VERSION 5.8 ;
BUSBITCHARS "[]" ;
DIVIDERCHAR "/" ;

UNITS
  DATABASE MICRONS 1000 ;
END UNITS

MANUFACTURINGGRID 0.005 ;

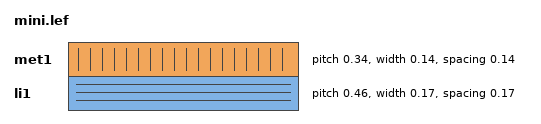
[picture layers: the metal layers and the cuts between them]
LAYER li1
  TYPE ROUTING ;
  DIRECTION HORIZONTAL ;
  PITCH 0.46 ;
  WIDTH 0.17 ;
  OFFSET 0.23 ;
  SPACING 0.17 ;
END li1

LAYER met1
  TYPE ROUTING ;
  DIRECTION VERTICAL ;
  PITCH 0.34 ;
  WIDTH 0.14 ;
  OFFSET 0.17 ;
  SPACING 0.14 ;
END met1

SITE unit
  CLASS CORE ;
  SIZE 0.46 BY 2.72 ;
  SYMMETRY Y ;
END unit

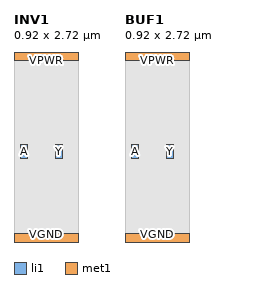
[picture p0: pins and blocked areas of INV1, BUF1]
MACRO INV1
  CLASS CORE ;
  ORIGIN 0 0 ;
  SIZE 0.92 BY 2.72 ;
  SITE unit ;
  PIN A
    DIRECTION INPUT ;
    USE SIGNAL ;
    PORT
      LAYER li1 ;
        RECT 0.1 1.2 0.2 1.4 ;
    END
  END A
  PIN Y
    DIRECTION OUTPUT ;
    USE SIGNAL ;
    PORT
      LAYER li1 ;
        RECT 0.6 1.2 0.7 1.4 ;
    END
  END Y
  PIN VPWR
    DIRECTION INOUT ;
    USE POWER ;
    SHAPE ABUTMENT ;
    PORT
      LAYER met1 ;
        RECT 0 2.6 0.92 2.72 ;
    END
  END VPWR
  PIN VGND
    DIRECTION INOUT ;
    USE GROUND ;
    SHAPE ABUTMENT ;
    PORT
      LAYER met1 ;
        RECT 0 0 0.92 0.12 ;
    END
  END VGND
  OBS
    LAYER li1 ;
      RECT 0 0 0.92 2.72 ;
  END
END INV1

MACRO BUF1
  CLASS CORE ;
  ORIGIN 0 0 ;
  SIZE 0.92 BY 2.72 ;
  SITE unit ;
  PIN A
    DIRECTION INPUT ;
    USE SIGNAL ;
    PORT
      LAYER li1 ;
        RECT 0.1 1.2 0.2 1.4 ;
    END
  END A
  PIN Y
    DIRECTION OUTPUT ;
    USE SIGNAL ;
    PORT
      LAYER li1 ;
        RECT 0.6 1.2 0.7 1.4 ;
    END
  END Y
  PIN VPWR
    DIRECTION INOUT ;
    USE POWER ;
    SHAPE ABUTMENT ;
    PORT
      LAYER met1 ;
        RECT 0 2.6 0.92 2.72 ;
    END
  END VPWR
  PIN VGND
    DIRECTION INOUT ;
    USE GROUND ;
    SHAPE ABUTMENT ;
    PORT
      LAYER met1 ;
        RECT 0 0 0.92 0.12 ;
    END
  END VGND
  OBS
    LAYER li1 ;
      RECT 0 0 0.92 2.72 ;
  END
END BUF1

END LIBRARY
